One B-rep face of a CAD part: STEP entity #541050.
In plain terms, the planar face has unit normal (0, -1, 0).
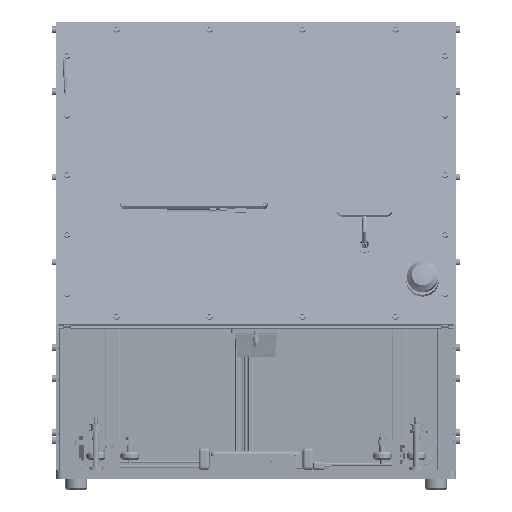
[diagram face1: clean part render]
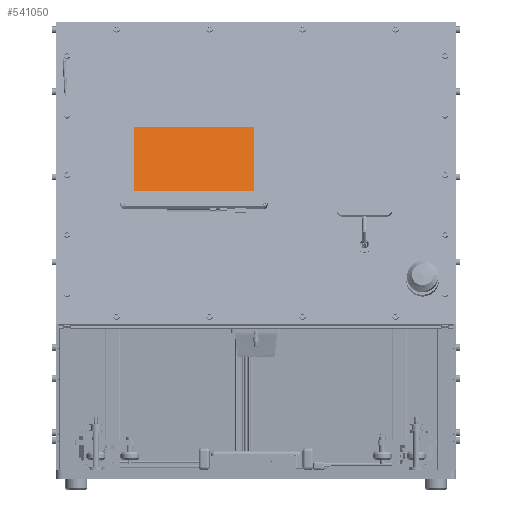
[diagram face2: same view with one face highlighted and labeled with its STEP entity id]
Its self-contained STEP definition (entity closure, numbers rounded to 3 decimals):
#540834 = EDGE_CURVE('',#540835,#540837,#540839,.T.);
#540835 = VERTEX_POINT('',#540836);
#540836 = CARTESIAN_POINT('',(-77.1,-1.45,-40.95));
#540837 = VERTEX_POINT('',#540838);
#540838 = CARTESIAN_POINT('',(-77.1,-1.45,44.95));
#540839 = SURFACE_CURVE('',#540840,(#540844,#540856),.PCURVE_S1.);
#540840 = LINE('',#540841,#540842);
#540841 = CARTESIAN_POINT('',(-77.1,-1.45,-40.95));
#540842 = VECTOR('',#540843,1.);
#540843 = DIRECTION('',(0.,0.,1.));
#540844 = PCURVE('',#540845,#540850);
#540845 = PLANE('',#540846);
#540846 = AXIS2_PLACEMENT_3D('',#540847,#540848,#540849);
#540847 = CARTESIAN_POINT('',(-77.1,-1.45,-40.95));
#540848 = DIRECTION('',(1.,0.,0.));
#540849 = DIRECTION('',(0.,0.,1.));
#540850 = DEFINITIONAL_REPRESENTATION('',(#540851),#540855);
#540851 = LINE('',#540852,#540853);
#540852 = CARTESIAN_POINT('',(0.,0.));
#540853 = VECTOR('',#540854,1.);
#540854 = DIRECTION('',(1.,0.));
#540855 = ( GEOMETRIC_REPRESENTATION_CONTEXT(2) 
PARAMETRIC_REPRESENTATION_CONTEXT() REPRESENTATION_CONTEXT('2D SPACE',''
  ) );
#540856 = PCURVE('',#540857,#540862);
#540857 = PLANE('',#540858);
#540858 = AXIS2_PLACEMENT_3D('',#540859,#540860,#540861);
#540859 = CARTESIAN_POINT('',(-77.1,-1.45,-40.95));
#540860 = DIRECTION('',(0.,1.,0.));
#540861 = DIRECTION('',(0.,0.,1.));
#540862 = DEFINITIONAL_REPRESENTATION('',(#540863),#540867);
#540863 = LINE('',#540864,#540865);
#540864 = CARTESIAN_POINT('',(0.,0.));
#540865 = VECTOR('',#540866,1.);
#540866 = DIRECTION('',(1.,0.));
#540867 = ( GEOMETRIC_REPRESENTATION_CONTEXT(2) 
PARAMETRIC_REPRESENTATION_CONTEXT() REPRESENTATION_CONTEXT('2D SPACE',''
  ) );
#540885 = PLANE('',#540886);
#540886 = AXIS2_PLACEMENT_3D('',#540887,#540888,#540889);
#540887 = CARTESIAN_POINT('',(-77.1,-1.45,-40.95));
#540888 = DIRECTION('',(0.,0.,1.));
#540889 = DIRECTION('',(1.,0.,0.));
#540939 = PLANE('',#540940);
#540940 = AXIS2_PLACEMENT_3D('',#540941,#540942,#540943);
#540941 = CARTESIAN_POINT('',(-77.1,-1.45,44.95));
#540942 = DIRECTION('',(0.,0.,1.));
#540943 = DIRECTION('',(1.,0.,0.));
#540954 = EDGE_CURVE('',#540955,#540957,#540959,.T.);
#540955 = VERTEX_POINT('',#540956);
#540956 = CARTESIAN_POINT('',(77.1,-1.45,-40.95));
#540957 = VERTEX_POINT('',#540958);
#540958 = CARTESIAN_POINT('',(77.1,-1.45,44.95));
#540959 = SURFACE_CURVE('',#540960,(#540964,#540976),.PCURVE_S1.);
#540960 = LINE('',#540961,#540962);
#540961 = CARTESIAN_POINT('',(77.1,-1.45,-40.95));
#540962 = VECTOR('',#540963,1.);
#540963 = DIRECTION('',(0.,0.,1.));
#540964 = PCURVE('',#540965,#540970);
#540965 = PLANE('',#540966);
#540966 = AXIS2_PLACEMENT_3D('',#540967,#540968,#540969);
#540967 = CARTESIAN_POINT('',(77.1,-1.45,-40.95));
#540968 = DIRECTION('',(1.,0.,0.));
#540969 = DIRECTION('',(0.,0.,1.));
#540970 = DEFINITIONAL_REPRESENTATION('',(#540971),#540975);
#540971 = LINE('',#540972,#540973);
#540972 = CARTESIAN_POINT('',(0.,0.));
#540973 = VECTOR('',#540974,1.);
#540974 = DIRECTION('',(1.,0.));
#540975 = ( GEOMETRIC_REPRESENTATION_CONTEXT(2) 
PARAMETRIC_REPRESENTATION_CONTEXT() REPRESENTATION_CONTEXT('2D SPACE',''
  ) );
#540976 = PCURVE('',#540857,#540977);
#540977 = DEFINITIONAL_REPRESENTATION('',(#540978),#540982);
#540978 = LINE('',#540979,#540980);
#540979 = CARTESIAN_POINT('',(0.,154.2));
#540980 = VECTOR('',#540981,1.);
#540981 = DIRECTION('',(1.,0.));
#540982 = ( GEOMETRIC_REPRESENTATION_CONTEXT(2) 
PARAMETRIC_REPRESENTATION_CONTEXT() REPRESENTATION_CONTEXT('2D SPACE',''
  ) );
#541050 = ADVANCED_FACE('',(#541051),#540857,.F.);
#541051 = FACE_BOUND('',#541052,.F.);
#541052 = EDGE_LOOP('',(#541053,#541074,#541075,#541096));
#541053 = ORIENTED_EDGE('',*,*,#541054,.F.);
#541054 = EDGE_CURVE('',#540835,#540955,#541055,.T.);
#541055 = SURFACE_CURVE('',#541056,(#541060,#541067),.PCURVE_S1.);
#541056 = LINE('',#541057,#541058);
#541057 = CARTESIAN_POINT('',(-77.1,-1.45,-40.95));
#541058 = VECTOR('',#541059,1.);
#541059 = DIRECTION('',(1.,0.,0.));
#541060 = PCURVE('',#540857,#541061);
#541061 = DEFINITIONAL_REPRESENTATION('',(#541062),#541066);
#541062 = LINE('',#541063,#541064);
#541063 = CARTESIAN_POINT('',(0.,0.));
#541064 = VECTOR('',#541065,1.);
#541065 = DIRECTION('',(0.,1.));
#541066 = ( GEOMETRIC_REPRESENTATION_CONTEXT(2) 
PARAMETRIC_REPRESENTATION_CONTEXT() REPRESENTATION_CONTEXT('2D SPACE',''
  ) );
#541067 = PCURVE('',#540885,#541068);
#541068 = DEFINITIONAL_REPRESENTATION('',(#541069),#541073);
#541069 = LINE('',#541070,#541071);
#541070 = CARTESIAN_POINT('',(0.,0.));
#541071 = VECTOR('',#541072,1.);
#541072 = DIRECTION('',(1.,0.));
#541073 = ( GEOMETRIC_REPRESENTATION_CONTEXT(2) 
PARAMETRIC_REPRESENTATION_CONTEXT() REPRESENTATION_CONTEXT('2D SPACE',''
  ) );
#541074 = ORIENTED_EDGE('',*,*,#540834,.T.);
#541075 = ORIENTED_EDGE('',*,*,#541076,.T.);
#541076 = EDGE_CURVE('',#540837,#540957,#541077,.T.);
#541077 = SURFACE_CURVE('',#541078,(#541082,#541089),.PCURVE_S1.);
#541078 = LINE('',#541079,#541080);
#541079 = CARTESIAN_POINT('',(-77.1,-1.45,44.95));
#541080 = VECTOR('',#541081,1.);
#541081 = DIRECTION('',(1.,0.,0.));
#541082 = PCURVE('',#540857,#541083);
#541083 = DEFINITIONAL_REPRESENTATION('',(#541084),#541088);
#541084 = LINE('',#541085,#541086);
#541085 = CARTESIAN_POINT('',(85.9,0.));
#541086 = VECTOR('',#541087,1.);
#541087 = DIRECTION('',(0.,1.));
#541088 = ( GEOMETRIC_REPRESENTATION_CONTEXT(2) 
PARAMETRIC_REPRESENTATION_CONTEXT() REPRESENTATION_CONTEXT('2D SPACE',''
  ) );
#541089 = PCURVE('',#540939,#541090);
#541090 = DEFINITIONAL_REPRESENTATION('',(#541091),#541095);
#541091 = LINE('',#541092,#541093);
#541092 = CARTESIAN_POINT('',(0.,0.));
#541093 = VECTOR('',#541094,1.);
#541094 = DIRECTION('',(1.,0.));
#541095 = ( GEOMETRIC_REPRESENTATION_CONTEXT(2) 
PARAMETRIC_REPRESENTATION_CONTEXT() REPRESENTATION_CONTEXT('2D SPACE',''
  ) );
#541096 = ORIENTED_EDGE('',*,*,#540954,.F.);
